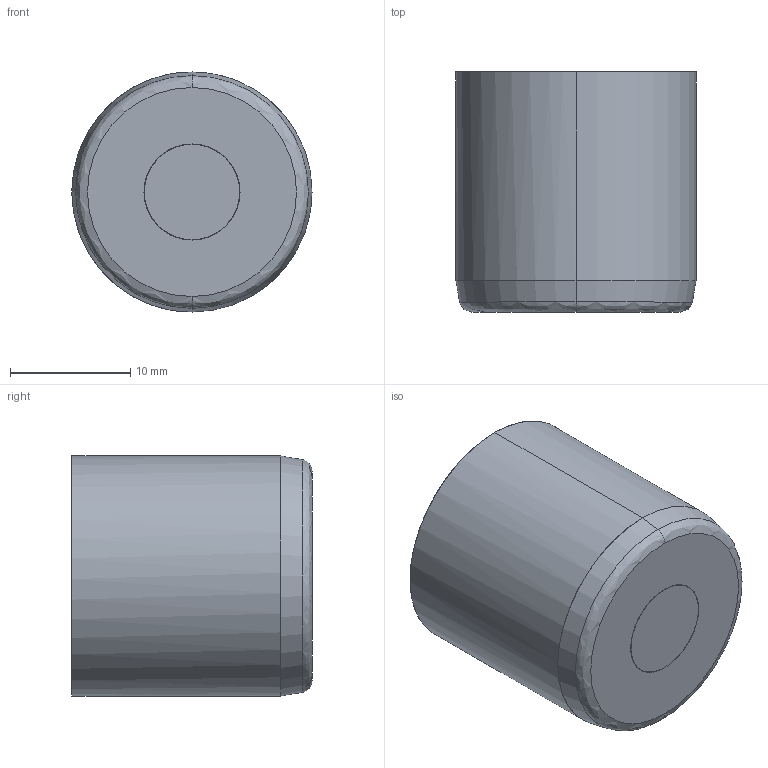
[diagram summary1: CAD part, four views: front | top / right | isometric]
IGES file: header records copied from the file, then geometry measured from it (millimetres).
Start section: START RECORD GO HERE.
Global section: file name: fa200710-21.igs; native system: DASSAULT SYSTEMES CATIA V5 R20 - www.3ds.com; preprocessor: CATIA Version 5 Release 20 ; author: Utente; organization: NB04-ASUS; date: 20201108.083432; units: millimetre
Bounding box: 20 x 20 x 20 mm (x, y, z)
Surface area: 3295.3 mm2 (no closed solid volume)
Topology: 0 solids, 0 shells, 473 faces, 2408 edges, 2406 vertices
Faces by surface type: bspline 255, plane 142, revolution 76
